(* Logix 5000 AddOnInstructionDefinition export SendSignMessage; software revision 17.00; part 3 of 3 *)
(* tags used below, declared in another part *)
   ENVariable4Message : BOOL;   // 0 = don't sent embedded variable 1 = send embedded variable
   ENVariableFormats : BOOL;   // 0 = no additional text formatting 1 = enable text formatting
   DN : BOOL;   // Instruction Interface Done Bit
   ER : BOOL;   // Instruction Interface Error Bit
   map_SignOutput : SINT[496];   // Ethernet/IP LEDSIGN.O Data I/O Mapping
   Packet1Sent : STRING;   // The actual packet sent to the sign (Packet1)
   Packet2Sent : STRING;   // The actual packet sent to the sign (Packet2)
   Packet3Sent : STRING;   // The actual packet sent to the sign (Packet3)
   Packet4Sent : STRING;   // The actual packet sent to the sign (Packet4)
   Packet5Sent : STRING;   // The actual packet sent to the sign (Packet5)
   Packet6Sent : STRING;   // The actual packet sent to the sign (Packet6)
   SEQ : DINT;   // Sequence Number
   InCycle : BOOL;   // Incycle
   Error : BOOL;   // Error
   Done : BOOL;   // Done
   SignETX : STRING;   // DO NOT EDIT = ^C
   Packet : STRING[7];   // Packet Array to send to sign
   SignVariable4 : STRING;
   Select : DINT;   // Packet Array Select
   TotalPacketCount : DINT[7];   // Total Character Count
   PacketMax : DINT;   // Max Packet Count
   Packet6Offset : DINT;
   Packet5Offset : DINT;
   Packet4Offset : DINT;
   Packet3Offset : DINT;
   Packet2Offset : DINT;
   Packet1Offset : DINT;
   SignVariableAttribute : STRING;
(* SendSignMessage, continued *)

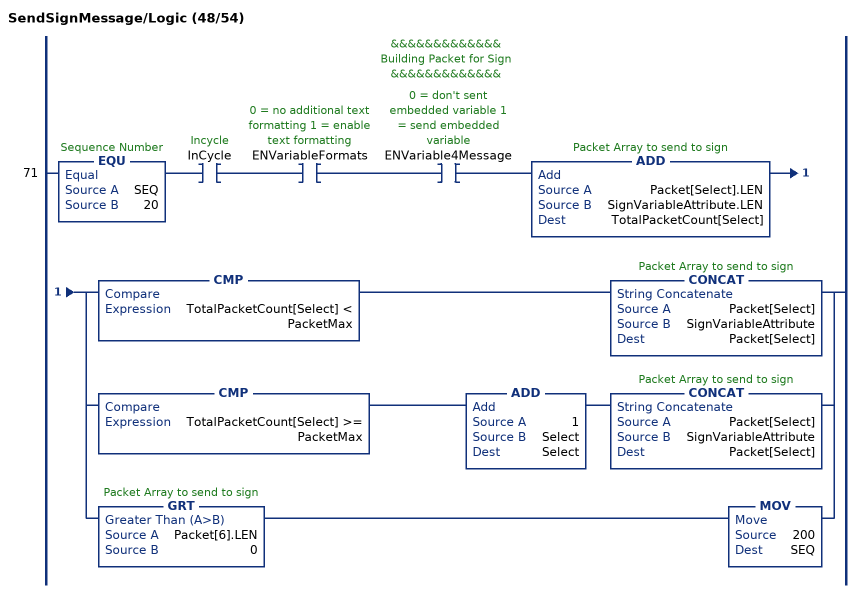
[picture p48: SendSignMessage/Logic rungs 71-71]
   // &&&&&&&&&&&&&
   // Building Packet for Sign
   // &&&&&&&&&&&&&
   71: EQU(SEQ,20)XIC(InCycle)XIC(ENVariableFormats)XIC(ENVariable4Message)ADD(Packet[Select].LEN,SignVariableAttribute.LEN,TotalPacketCount[Select])[CMP(TotalPacketCount[Select] < PacketMax) CONCAT(Packet[Select],SignVariableAttribute,Packet[Select]) ,CMP(TotalPacketCount[Select] >= PacketMax) ADD(1,Select,Select) CONCAT(Packet[Select],SignVariableAttribute,Packet[Select]) ,GRT(Packet[6].LEN,0) MOV(200,SEQ) ];
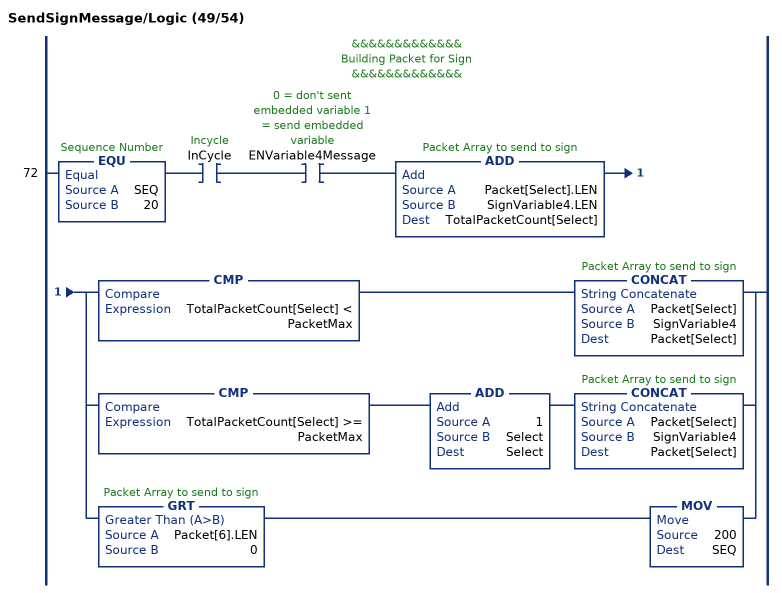
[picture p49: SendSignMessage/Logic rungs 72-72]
   // &&&&&&&&&&&&&
   // Building Packet for Sign
   // &&&&&&&&&&&&&
   72: EQU(SEQ,20)XIC(InCycle)XIC(ENVariable4Message)ADD(Packet[Select].LEN,SignVariable4.LEN,TotalPacketCount[Select])[CMP(TotalPacketCount[Select] < PacketMax) CONCAT(Packet[Select],SignVariable4,Packet[Select]) ,CMP(TotalPacketCount[Select] >= PacketMax) ADD(1,Select,Select) CONCAT(Packet[Select],SignVariable4,Packet[Select]) ,GRT(Packet[6].LEN,0) MOV(200,SEQ) ];
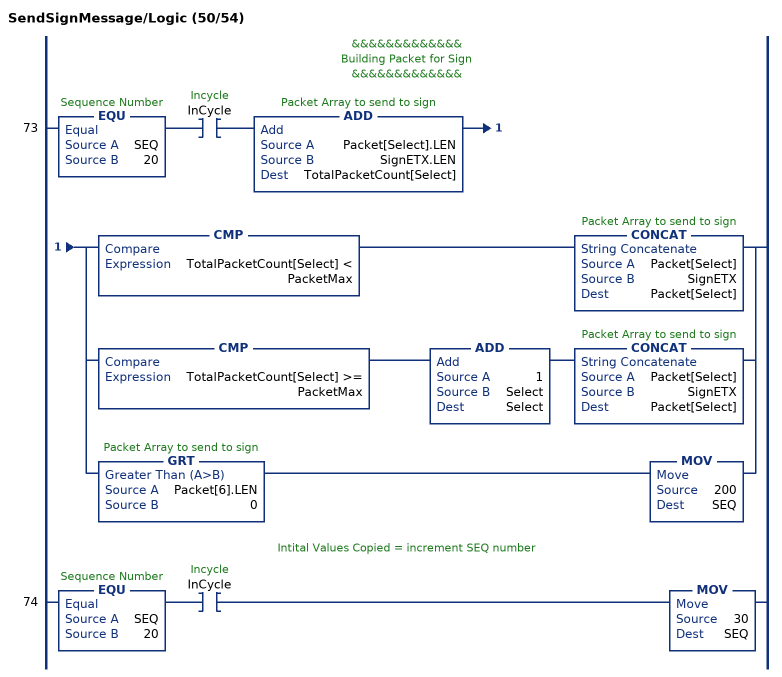
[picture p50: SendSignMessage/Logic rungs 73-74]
   // &&&&&&&&&&&&&
   // Building Packet for Sign
   // &&&&&&&&&&&&&
   73: EQU(SEQ,20)XIC(InCycle)ADD(Packet[Select].LEN,SignETX.LEN,TotalPacketCount[Select])[CMP(TotalPacketCount[Select] < PacketMax) CONCAT(Packet[Select],SignETX,Packet[Select]) ,CMP(TotalPacketCount[Select] >= PacketMax) ADD(1,Select,Select) CONCAT(Packet[Select],SignETX,Packet[Select]) ,GRT(Packet[6].LEN,0) MOV(200,SEQ) ];
   // Intital Values Copied = increment SEQ number
   74: EQU(SEQ,20)XIC(InCycle)MOV(30,SEQ);
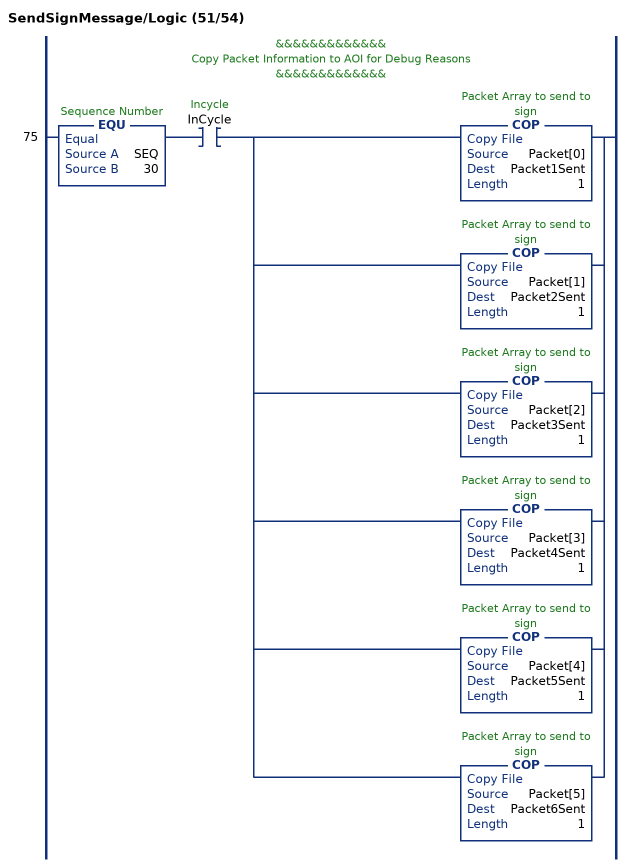
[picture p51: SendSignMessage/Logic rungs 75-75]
   // &&&&&&&&&&&&&
   // Copy Packet Information to AOI for Debug Reasons
   // &&&&&&&&&&&&&
   75: EQU(SEQ,30)XIC(InCycle)[COP(Packet[0],Packet1Sent,1) ,COP(Packet[1],Packet2Sent,1) ,COP(Packet[2],Packet3Sent,1) ,COP(Packet[3],Packet4Sent,1) ,COP(Packet[4],Packet5Sent,1) ,COP(Packet[5],Packet6Sent,1) ];
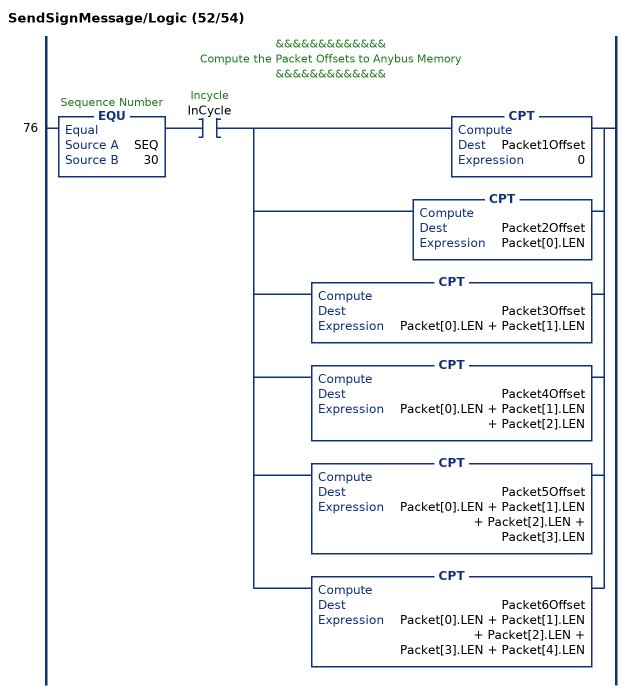
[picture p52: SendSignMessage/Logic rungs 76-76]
   // &&&&&&&&&&&&&
   // Compute the Packet Offsets to Anybus Memory
   // &&&&&&&&&&&&&
   76: EQU(SEQ,30)XIC(InCycle)[CPT(Packet1Offset,0) ,CPT(Packet2Offset,Packet[0].LEN) ,CPT(Packet3Offset,Packet[0].LEN + Packet[1].LEN) ,CPT(Packet4Offset,Packet[0].LEN + Packet[1].LEN + Packet[2].LEN) ,CPT(Packet5Offset,Packet[0].LEN + Packet[1].LEN + Packet[2].LEN + Packet[3].LEN) ,CPT(Packet6Offset,Packet[0].LEN + Packet[1].LEN + Packet[2].LEN + Packet[3].LEN + Packet[4].LEN) ];
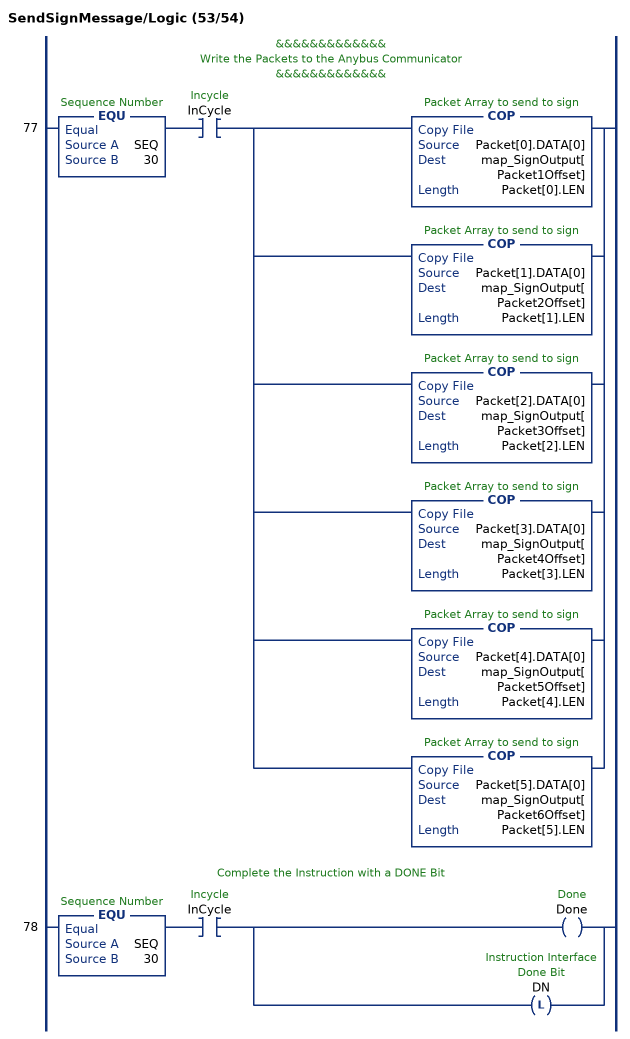
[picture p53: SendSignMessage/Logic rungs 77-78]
   // &&&&&&&&&&&&&
   // Write the Packets to the Anybus Communicator
   // &&&&&&&&&&&&&
   77: EQU(SEQ,30)XIC(InCycle)[COP(Packet[0].DATA[0],map_SignOutput[Packet1Offset],Packet[0].LEN) ,COP(Packet[1].DATA[0],map_SignOutput[Packet2Offset],Packet[1].LEN) ,COP(Packet[2].DATA[0],map_SignOutput[Packet3Offset],Packet[2].LEN) ,COP(Packet[3].DATA[0],map_SignOutput[Packet4Offset],Packet[3].LEN) ,COP(Packet[4].DATA[0],map_SignOutput[Packet5Offset],Packet[4].LEN) ,COP(Packet[5].DATA[0],map_SignOutput[Packet6Offset],Packet[5].LEN) ];
   // Complete the Instruction with a DONE Bit
   78: EQU(SEQ,30)XIC(InCycle)[OTE(Done) ,OTL(DN) ];
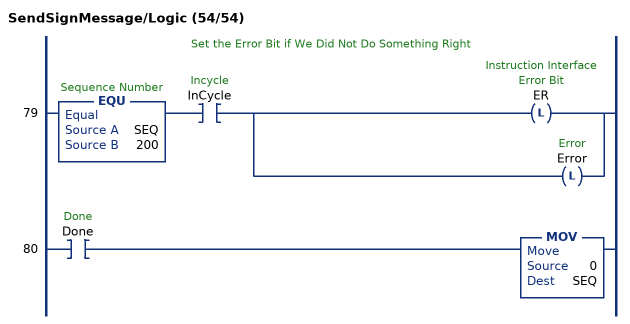
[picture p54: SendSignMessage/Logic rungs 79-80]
   // Set the Error Bit if We Did Not Do Something Right
   79: EQU(SEQ,200)XIC(InCycle)[OTL(ER) ,OTL(Error) ];
   80: XIC(Done)MOV(0,SEQ);
END_ROUTINE
END_ADD_ON_INSTRUCTION
